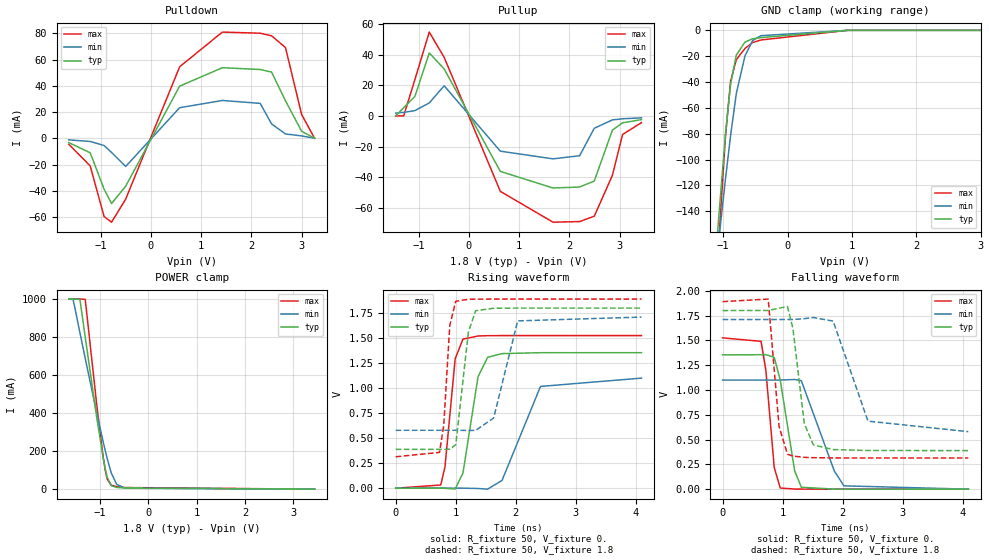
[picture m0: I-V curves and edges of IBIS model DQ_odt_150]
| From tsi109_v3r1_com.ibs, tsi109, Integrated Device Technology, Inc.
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|   MODEL DQ_odt_150
[Model]   DQ_odt_150
Model_type  I/O
Polarity   Non-Inverting
Enable   Active-Low
|   typ   min   max
|C_comp_off 3.662p 3.711p 3.594p
|C_comp_on 3.698p 3.62p 3.948p
C_comp 3.68p 3.665p 3.771p
Cref  =   20pF
Vmeas =   0.9v
Vinl  =   0.650v
Vinh  =   1.150v
[Model Spec]
[Temperature Range]   25   125   0
[Voltage Range] 1.8 1.71 1.89
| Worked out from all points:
|   slope of the pulldown table from 0 to 0.27 V, typ, clamps not added: 14 ohm
|   slope of the pullup table from 0 to 0.27 V, typ, clamps not added: 16.6 ohm
|   rising waveform, R_fixture 50, V_fixture 0.: 20-80 % time 205ps typ, 380ps min, 137ps max; typ from 0 V to 1.35 V
|   rising waveform, R_fixture 50, V_fixture 1.8: 20-80 % time 121ps typ, 188ps min, 93.3ps max; typ from 0.389 V to 1.8 V
|   falling waveform, R_fixture 50, V_fixture 0.: 20-80 % time 211ps typ, 348ps min, 129ps max; typ from 1.35 V to 0 V
|   falling waveform, R_fixture 50, V_fixture 1.8: 20-80 % time 164ps typ, 316ps min, 113ps max; typ from 1.8 V to 0.389 V
[Pulldown]
-1.636V   -3.323mA   -1.212mA   -4.599mA
-1.21V    -11.07mA   -2.446mA   -21.09mA
-933.3mV  -38.78mA   -5.524mA   -59.65mA
-784.8mV  -49.73mA   -10.81mA   -63.97mA
-502.6mV  -36.5mA    -21.48mA   -46.35mA
571.6mV   39.71mA    23.3mA     54.46mA
1.423V    53.79mA    28.81mA    80.93mA
2.176V    52.4mA     26.59mA    80.07mA
2.403V    50.45mA    10.95mA    78.12mA
2.68V     28.57mA    3.287mA    69.15mA
3.002V    5.316mA    1.795mA    18.12mA
3.26V     0A         0A         0A
[Pullup]
-1.46V    0A         1.84mA     0A
-1.301V   5.351mA    2.288mA    0A
-1.078V   12.65mA    3.443mA    23.66mA
-791.3mV  41.1mA     8.484mA    54.75mA
-494.3mV  30.7mA     19.67mA    38.23mA
624.5mV   -36.24mA   -23.04mA   -49.29mA
1.674V    -47.11mA   -28.05mA   -69.43mA
2.204V    -46.44mA   -26.01mA   -69.03mA
2.496V    -42.58mA   -8.056mA   -65.51mA
2.857V    -9.27mA    -2.618mA   -38.81mA
3.06V     -4.507mA   -1.881mA   -12.14mA
3.436V    -2.406mA   -1.258mA   -4.39mA
[GND Clamp]
-1.636V   -544mA     -441.4mA   -680mA
-1.124V   -180.9mA   -188.5mA   -209.5mA
-1.099V   -164.3mA   -176.7mA   -188.1mA
-1.074V   -147.9mA   -165mA     -167.2mA
-964.3mV  -80.44mA   -115.2mA   -82.44mA
-884.7mV  -41.57mA   -81.42mA   -39.48mA
-795.1mV  -19.11mA   -48.76mA   -22.6mA
-660.7mV  -9.028mA   -19.65mA   -14.03mA
-541.2mV  -6.508mA   -7.863mA   -9.392mA
-411.8mV  -5.625mA   -4.125mA   -7.467mA
937.8mV   0A         0A         0A
3.26V     0A         0A         0A
[Power Clamp]
-1.636V   1A         1A         1A
-1.546V   1A         997.3mA    1A
-1.407V   998.2mA    823.6mA    1A
-1.297V   799.4mA    687.6mA    998.5mA
-1.063V   382.4mA    404.2mA    451.3mA
-928mV    166.1mA    250.1mA    171.6mA
-883.1mV  105.4mA    201.6mA    98.24mA
-843.2mV  61.99mA    160.6mA    52.13mA
-758.4mV  18mA       84.13mA    19.98mA
-648.7mV  9.117mA    25.5mA     13.77mA
-474.1mV  6.076mA    5.11mA     8.511mA
3.436V    0A         0A         0A
[Ramp]
dV/dt_r .812/205.375p .66/380.602p .915/136.332p
dV/dt_f .847/163.938p .679/315.888p .946/112.754p
[Rising Waveform]
R_fixture = 50
V_fixture = 0.
0s        0V         0V         0V
750ps     198.9uV    -789.9nV   31.79mV
820ps     -1.136mV   10.99uV    212.1mV
990ps     -8.18mV    142.4uV    1.294V
1.12ns    152.2mV    239.9uV    1.49V
1.37ns    1.113V     -2.911mV   1.521V
1.53ns    1.308V     -9.701mV   1.524V
1.77ns    1.345V     78.26mV    1.525V
2.41ns    1.354V     1.017V     1.525V
4.09ns    1.354V     1.1V       1.525V
[Rising Waveform]
R_fixture = 50
V_fixture = 1.8
V_fixture_min = 1.71
V_fixture_max = 1.89
0s        388.5mV    578.6mV    314.1mV
730ps     388.1mV    578.7mV    357.9mV
800ps     387.6mV    578.7mV    630.1mV
900ps     389.8mV    578.7mV    1.627V
1ns       434.4mV    578.6mV    1.868V
1.21ns    1.561V     577.2mV    1.888V
1.33ns    1.773V     577.6mV    1.889V
1.63ns    1.798V     701.1mV    1.89V
2.03ns    1.8V       1.672V     1.89V
4.09ns    1.8V       1.71V      1.89V
[Falling Waveform]
R_fixture = 50
V_fixture = 0.
0s        1.354V     1.1V       1.525V
640ps     1.355V     1.1V       1.49V
720ps     1.356V     1.1V       1.203V
860ps     1.329V     1.1V       217.9mV
960ps     1.099V     1.1V       11.48mV
1.2ns     183.3mV    1.105V     1.23mV
1.31ns    19.37mV    1.094V     714.3uV
1.86ns    480.7uV    183.1mV    48.69uV
2.02ns    258.4uV    33.45mV    22.5uV
4.09ns    0V         23.14uV    0V
[Falling Waveform]
R_fixture = 50
V_fixture = 1.8
V_fixture_min = 1.71
V_fixture_max = 1.89
0s        1.8V       1.71V      1.89V
760ps     1.801V     1.71V      1.916V
940ps     1.824V     1.71V      632.1mV
1.08ns    1.84V      1.71V      351.9mV
1.17ns    1.623V     1.71V      333.6mV
1.36ns    662.2mV    1.718V     320.8mV
1.51ns    446.5mV    1.73V      317.2mV
1.84ns    399.2mV    1.694V     314.7mV
2.42ns    389.6mV    685.4mV    314.2mV
4.09ns    388.5mV    579.6mV    314.1mV
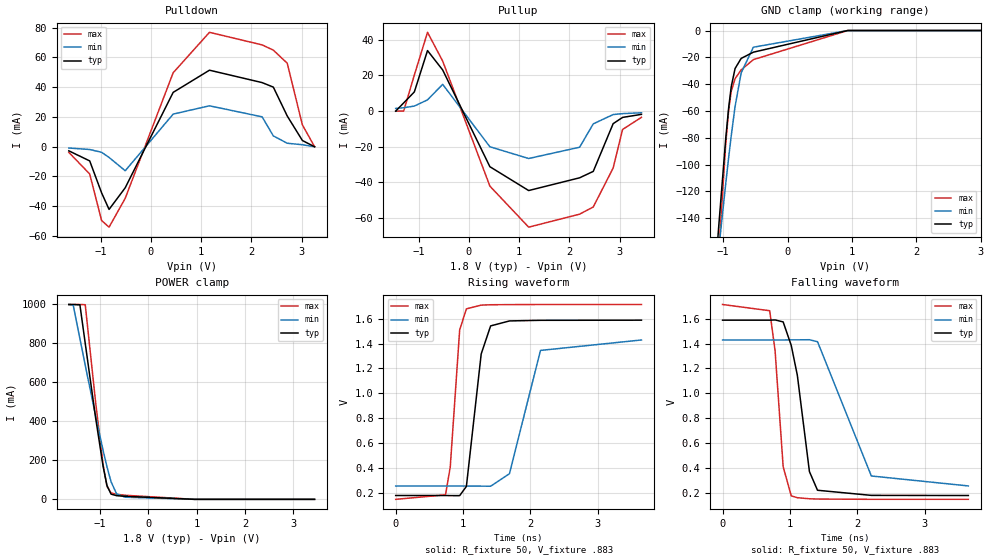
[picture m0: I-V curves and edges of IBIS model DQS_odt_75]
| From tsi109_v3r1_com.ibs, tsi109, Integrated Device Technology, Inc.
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|   MODEL DQS_odt_75
[Model]   DQS_odt_75
Model_type  I/O
Polarity   Non-Inverting
Enable   Active-Low
|   typ   min   max
|C_comp_off 3.406p 3.446p 3.36p
|C_comp_on 3.3p 3.205p 3.514p
C_comp 3.353p 3.325p 3.437p
Cref  =   20pF
Vmeas =   0.9v
Vinl  =   0.650v
Vinh  =   1.150v
[Model Spec]
[Temperature Range]   25   125   0
[Voltage Range] 1.8 1.71 1.89
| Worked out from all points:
|   slope of the pulldown table from 0 to 0.27 V, typ, clamps not added: 15.5 ohm
|   slope of the pullup table from 0 to 0.27 V, typ, clamps not added: 18.7 ohm
|   rising waveform, R_fixture 50, V_fixture .883: 20-80 % time 155ps typ, 260ps min, 111ps max; typ from 0.179 V to 1.59 V
|   falling waveform, R_fixture 50, V_fixture .883: 20-80 % time 211ps typ, 436ps min, 121ps max; typ from 1.59 V to 0.179 V
[Pulldown]
-1.636V   -2.749mA   -869.2uA   -3.779mA
-1.22V    -9.523mA   -1.848mA   -18.31mA
-982.8mV  -30.99mA   -3.738mA   -49.62mA
-834.2mV  -42.14mA   -7.191mA   -54.06mA
-512.5mV  -27.58mA   -16.15mA   -34.67mA
442.9mV   36.55mA    21.94mA    49.75mA
1.166V    51.46mA    27.52mA    76.92mA
2.215V    43.12mA    20.1mA     68.47mA
2.438V    40.09mA    7.284mA    64.95mA
2.715V    20.68mA    2.355mA    56.15mA
3.017V    4.187mA    1.352mA    14.69mA
3.26V     0A         0A         0A
[Pullup]
-1.46V    0A         1.493mA    0A
-1.301V   4.568mA    1.878mA    0A
-1.088V   10.76mA    2.811mA    20.24mA
-826mV    33.9mA     6.297mA    44.13mA
-524mV    23.04mA    14.98mA    28.03mA
416.5mV   -31.17mA   -19.99mA   -42.04mA
1.189V    -44.52mA   -26.57mA   -65.03mA
2.204V    -37.38mA   -20.25mA   -57.75mA
2.476V    -33.78mA   -7.136mA   -53.72mA
2.872V    -7.045mA   -1.945mA   -31.9mA
3.06V     -3.537mA   -1.423mA   -10.29mA
3.436V    -1.832mA   -944.9uA   -3.489mA
[GND Clamp]
-1.636V   -544.5mA   -441.7mA   -680.8mA
-1.123V   -182.1mA   -189mA     -211.5mA
-1.098V   -165.6mA   -177.3mA   -190.4mA
-1.074V   -149.3mA   -165.6mA   -169.7mA
-959.1mV  -80.05mA   -113.8mA   -84.1mA
-914.3mV  -57.55mA   -94.64mA   -59.42mA
-874.4mV  -41.91mA   -78.49mA   -45.25mA
-814.7mV  -28.31mA   -56.62mA   -35.88mA
-720.1mV  -20.78mA   -31.57mA   -29.35mA
-530.9mV  -16.15mA   -12.45mA   -21.7mA
935.2mV   0A         0A         0A
3.26V     0A         0A         0A
[Power Clamp]
-1.636V   1A         1A         1A
-1.546V   1A         997.4mA    1A
-1.407V   998.4mA    824mA      1A
-1.297V   800.3mA    688.1mA    998.9mA
-1.083V   418.1mA    428.5mA    498.6mA
-928.2mV  168.8mA    251.1mA    176.9mA
-848.4mV  71mA       166.8mA    66.16mA
-763.6mV  26.63mA    89.57mA    32.79mA
-648.9mV  18.72mA    27.94mA    26.18mA
-474.4mV  15.54mA    10.87mA    20.84mA
954.8mV   0A         0A         0A
3.436V    0A         0A         0A
[Ramp]
dV/dt_r .845/154.678p .705/260.261p .939/110.93p
dV/dt_f .845/210.589p .705/436.081p .939/121.27p
[Rising Waveform]
R_fixture = 50
V_fixture = .883
V_fixture_min = .842
V_fixture_max = .931
0s        179.2mV    255.2mV    148.5mV
740ps     179.2mV    255.2mV    184.6mV
810ps     178.4mV    255.2mV    406.7mV
950ps     178.3mV    255.3mV    1.509V
1.05ns    252.2mV    255.2mV    1.679V
1.27ns    1.317V     254.5mV    1.709V
1.41ns    1.542V     253.8mV    1.712V
1.69ns    1.582V     354.6mV    1.713V
2.15ns    1.587V     1.345V     1.714V
3.65ns    1.588V     1.429V     1.714V
[Falling Waveform]
R_fixture = 50
V_fixture = .883
V_fixture_min = .842
V_fixture_max = .931
0s        1.588V     1.429V     1.714V
700ps     1.588V     1.429V     1.664V
780ps     1.59V      1.429V     1.342V
900ps     1.574V     1.429V     410.3mV
1.02ns    1.385V     1.43V      176.4mV
1.11ns    1.147V     1.43V      161.6mV
1.29ns    371.6mV    1.431V     153mV
1.41ns    221.4mV    1.415V     150.8mV
2.21ns    180.2mV    336.1mV    148.5mV
3.65ns    179.2mV    256.1mV    148.5mV
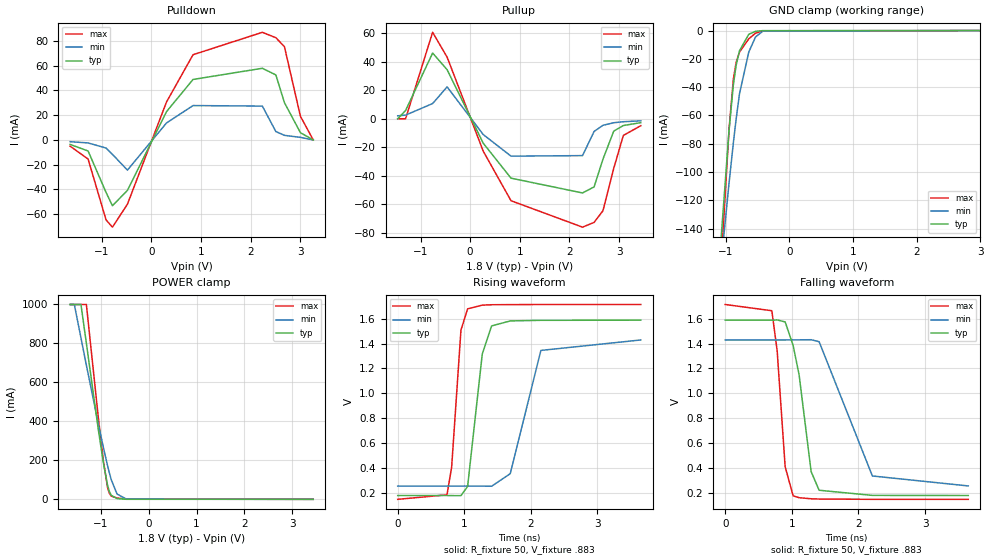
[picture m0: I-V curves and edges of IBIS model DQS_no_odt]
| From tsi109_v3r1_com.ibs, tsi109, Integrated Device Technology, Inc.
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|   MODEL DQS_no_odt
[Model]   DQS_no_odt
Model_type  I/O
Polarity   Non-Inverting
Enable   Active-Low
|   typ   min   max
|C_comp_off 3.963p 4.018p 3.887p
|C_comp_on 3.3p 3.205p 3.514p
C_comp 3.631p 3.611p 3.7p
Cref  =   20pF
Vmeas =   0.9v
Vinl  =   0.650v
Vinh  =   1.150v
[Model Spec]
[Temperature Range]   25   125   0
[Voltage Range] 1.8 1.71 1.89
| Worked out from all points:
|   slope of the pulldown table from 0 to 0.27 V, typ, clamps not added: 13.2 ohm
|   slope of the pullup table from 0 to 0.27 V, typ, clamps not added: 15.4 ohm
|   GND clamp passes 1 mA (typ) near -0.57 V on its own axis
|   POWER clamp passes 1 mA (typ) near -0.54 V on its own axis
|   rising waveform, R_fixture 50, V_fixture .883: 20-80 % time 155ps typ, 260ps min, 111ps max; typ from 0.179 V to 1.59 V
|   falling waveform, R_fixture 50, V_fixture .883: 20-80 % time 211ps typ, 436ps min, 121ps max; typ from 1.59 V to 0.179 V
[Pulldown]
-1.636V   -3.649mA   -1.42mA    -5.055mA
-1.275V   -8.922mA   -2.436mA   -15.46mA
-913.5mV  -42.38mA   -6.562mA   -64.55mA
-784.8mV  -53.15mA   -11.67mA   -70.44mA
-482.8mV  -40.74mA   -24.38mA   -51.92mA
304.3mV   22.85mA    13.69mA    30.62mA
838.9mV   48.83mA    27.75mA    68.81mA
2.235V    57.86mA    27.32mA    86.89mA
2.507V    52.5mA     6.75mA     82.54mA
2.68V     30.08mA    3.705mA    75.24mA
3.002V    5.838mA    2.051mA    19.08mA
3.26V     0A         0A         0A
[Pullup]
-1.46V    0A         2.056mA    0A
-1.301V   5.791mA    2.542mA    0A
-756.7mV  46.08mA    10.65mA    60.6mA
-464.6mV  34.39mA    22.34mA    43.2mA
263.1mV   -17.14mA   -11.08mA   -22.74mA
822.5mV   -41.66mA   -26.22mA   -57.48mA
2.263V    -52.03mA   -25.85mA   -76.01mA
2.496V    -47.78mA   -8.921mA   -72.68mA
2.674V    -28.4mA    -4.593mA   -64.52mA
2.892V    -8.672mA   -2.791mA   -34.76mA
3.085V    -4.751mA   -2.084mA   -11.69mA
3.436V    -2.732mA   -1.461mA   -4.887mA
[GND Clamp]
-1.636V   -543.7mA   -441.2mA   -679.6mA
-1.113V   -173.3mA   -183.3mA   -199.6mA
-1.089V   -157.2mA   -171.9mA   -178.9mA
-1.065V   -141.4mA   -160.5mA   -158.5mA
-948.9mV  -70.59mA   -107.9mA   -69.79mA
-881.1mV  -38.31mA   -79.34mA   -34.33mA
-837.5mV  -24.54mA   -62.52mA   -22.45mA
-784.3mV  -14.23mA   -44.56mA   -15.18mA
-639mV    -2.666mA   -15.21mA   -5.883mA
-532.5mV  -543.1uA   -4.536mA   -1.841mA
-416.4mV  -69.24uA   -425.6uA   -218.8uA
3.26V     0A         0A         0A
[Power Clamp]
-1.636V   1A         1A         1A
-1.549V   1A         1A         1A
-1.411V   1A         828.4mA    1A
-1.298V   800.8mA    688.6mA    1A
-1.047V   355mA      385.4mA    415.3mA
-944.5mV  189.4mA    267.9mA    200.5mA
-857.4mV  74.25mA    174.4mA    62.22mA
-821.5mV  42.19mA    138.8mA    31.99mA
-780.5mV  20.7mA     101.5mA    16.68mA
-657.5mV  3.818mA    26.99mA    6.851mA
-462.8mV  270uA      1.332mA    1.058mA
3.436V    0A         0A         0A
[Ramp]
dV/dt_r .845/154.678p .705/260.261p .939/110.93p
dV/dt_f .845/210.589p .705/436.081p .939/121.27p
[Rising Waveform]
R_fixture = 50
V_fixture = .883
V_fixture_min = .842
V_fixture_max = .931
0s        179.2mV    255.2mV    148.5mV
740ps     179.2mV    255.2mV    184.6mV
810ps     178.4mV    255.2mV    406.7mV
950ps     178.3mV    255.3mV    1.509V
1.05ns    252.2mV    255.2mV    1.679V
1.27ns    1.317V     254.5mV    1.709V
1.41ns    1.542V     253.8mV    1.712V
1.69ns    1.582V     354.6mV    1.713V
2.15ns    1.587V     1.345V     1.714V
3.65ns    1.588V     1.429V     1.714V
[Falling Waveform]
R_fixture = 50
V_fixture = .883
V_fixture_min = .842
V_fixture_max = .931
0s        1.588V     1.429V     1.714V
700ps     1.588V     1.429V     1.664V
780ps     1.59V      1.429V     1.342V
900ps     1.574V     1.429V     410.3mV
1.02ns    1.385V     1.43V      176.4mV
1.11ns    1.147V     1.43V      161.6mV
1.29ns    371.6mV    1.431V     153mV
1.41ns    221.4mV    1.415V     150.8mV
2.21ns    180.2mV    336.1mV    148.5mV
3.65ns    179.2mV    256.1mV    148.5mV
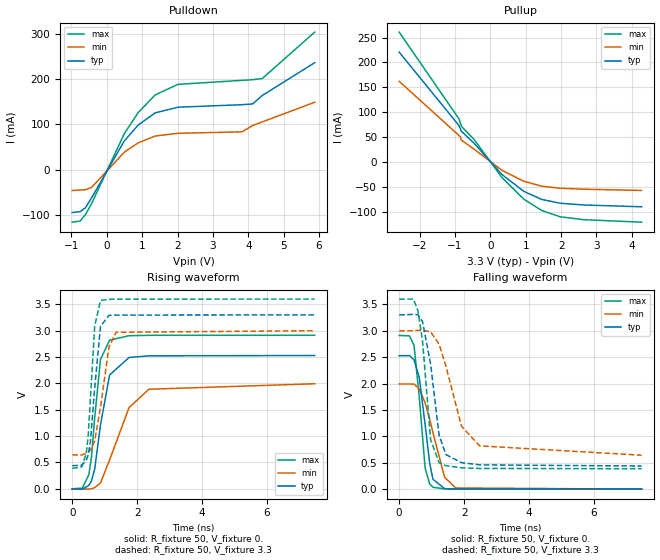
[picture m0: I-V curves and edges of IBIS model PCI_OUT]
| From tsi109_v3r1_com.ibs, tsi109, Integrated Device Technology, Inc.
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|   MODEL PCI_OUT
[Model]   PCI_OUT
Model_type  Output
C_comp 4.536p 4.267p 4.874p
Polarity   Non-Inverting
Enable   Active-High
Vmeas =   1.50V
Cref =   10pF
Rref =   50
Vref=   0.0V
[Model Spec]
[Temperature Range]   25.0   125.0   0.0
[POWER Clamp Reference]   3.30V   3.00V   3.60V
[GND Clamp Reference]   0.00V   0.00V   0.00V
[Voltage Range] 3.3 3. 3.6
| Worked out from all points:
|   slope of the pulldown table from 0 to 0.495 V, typ, clamps not added: 7.81 ohm
|   slope of the pullup table from 0 to 0.495 V, typ, clamps not added: 13.9 ohm
|   rising waveform, R_fixture 50, V_fixture 0.: 20-80 % time 365ps typ, 722ps min, 252ps max; typ from 0 V to 2.53 V
|   rising waveform, R_fixture 50, V_fixture 3.3: 20-80 % time 214ps typ, 317ps min, 179ps max; typ from 0.438 V to 3.3 V
|   falling waveform, R_fixture 50, V_fixture 0.: 20-80 % time 295ps typ, 484ps min, 225ps max; typ from 2.53 V to 0 V
|   falling waveform, R_fixture 50, V_fixture 3.3: 20-80 % time 338ps typ, 623ps min, 255ps max; typ from 3.3 V to 0.438 V
[Pulldown]
-976.9mV  -94.66mA   -46.06mA   -115.9mA
-755.1mV  -92.67mA   -44.99mA   -113.3mA
-602.6mV  -83.91mA   -44.25mA   -98.97mA
-429.3mV  -61.97mA   -39.17mA   -74.63mA
492.7mV   63.11mA    38.33mA    79.1mA
887.8mV   98.31mA    59.1mA     125.8mA
1.366V    125.1mA    74.02mA    164.6mA
2.011V    137.6mA    80.08mA    188mA
3.82V     143.1mA    83.35mA    196.8mA
4.125V    144.9mA    97.25mA    198.3mA
4.395V    163.4mA    105.2mA    200.8mA
5.879V    235.8mA    148.6mA    303.2mA
[Pullup]
-2.579V   220.8mA    162.3mA    261mA
-887.4mV  73.58mA    53.57mA    86.96mA
-845.8mV  67.08mA    50.84mA    78.03mA
-825mV    62.16mA    44.44mA    73.93mA
-797.3mV  60.62mA    43.09mA    70.27mA
-457.6mV  37.9mA     26.06mA    45.41mA
325.7mV   -24.64mA   -16.22mA   -30.66mA
942.6mV   -58.4mA    -38.19mA   -74.08mA
1.449V    -74.68mA   -48.2mA    -96.82mA
1.969V    -82.31mA   -52.22mA   -109.5mA
2.641V    -85.87mA   -54.22mA   -115.4mA
4.277V    -89.5mA    -56.68mA   -120.4mA
[Ramp]
dV/dt_r 1.518/365.233p 1.196/721.027p 1.748/252.143p
dV/dt_f 1.717/337.435p 1.415/622.991p 1.928/255.277p
[Rising Waveform]
R_fixture = 50
V_fixture = 0.
0s        0V         0V         0V
310ps     -6.844mV   -4.37mV    13.04mV
510ps     64.12mV    -5.727mV   266.9mV
590ps     148.6mV    876.9uV    593.8mV
690ps     372.2mV    21.72mV    1.349V
870ps     1.216V     113.8mV    2.456V
1.15ns    2.159V     548.1mV    2.82V
1.75ns    2.492V     1.542V     2.905V
2.36ns    2.523V     1.889V     2.912V
7.47ns    2.529V     1.993V     2.913V
[Rising Waveform]
R_fixture = 50
V_fixture = 3.3
V_fixture_min = 3.
V_fixture_max = 3.6
0s        438.2mV    642.1mV    387.4mV
290ps     446mV      642.8mV    414mV
430ps     538.7mV    670.7mV    668.8mV
490ps     644.8mV    695.1mV    995.8mV
560ps     900.2mV    739mV      1.723V
690ps     1.912V     905.9mV    3.085V
870ps     3.083V     1.55V      3.573V
1.13ns    3.29V      2.691V     3.595V
1.35ns    3.296V     2.969V     3.598V
7.47ns    3.3V       3V         3.6V
[Falling Waveform]
R_fixture = 50
V_fixture = 0.
0s        2.529V     1.993V     2.913V
320ps     2.53V      1.993V     2.904V
460ps     2.449V     1.991V     2.721V
620ps     2.114V     1.898V     1.741V
800ps     1.225V     1.639V     400.5mV
940ps     494.5mV    1.326V     98.54mV
1.04ns    189.4mV    1.072V     36.42mV
1.4ns     9.436mV    226.5mV    4.559mV
1.74ns    3.211mV    22.96mV    1.848mV
7.47ns    1.068uV    15.07uV    0V
[Falling Waveform]
R_fixture = 50
V_fixture = 3.3
V_fixture_min = 3.
V_fixture_max = 3.6
0s        3.3V       3V         3.6V
440ps     3.312V     3.002V     3.602V
580ps     3.305V     3.009V     3.381V
720ps     3.177V     3.011V     2.812V
970ps     2.367V     2.981V     935.2mV
1.23ns    1.023V     2.749V     502.3mV
1.44ns    655.6mV    2.332V     445.3mV
1.92ns    502.3mV    1.193V     404.6mV
2.48ns    460.6mV    820.5mV    392.7mV
7.47ns    438.2mV    643.1mV    387.4mV
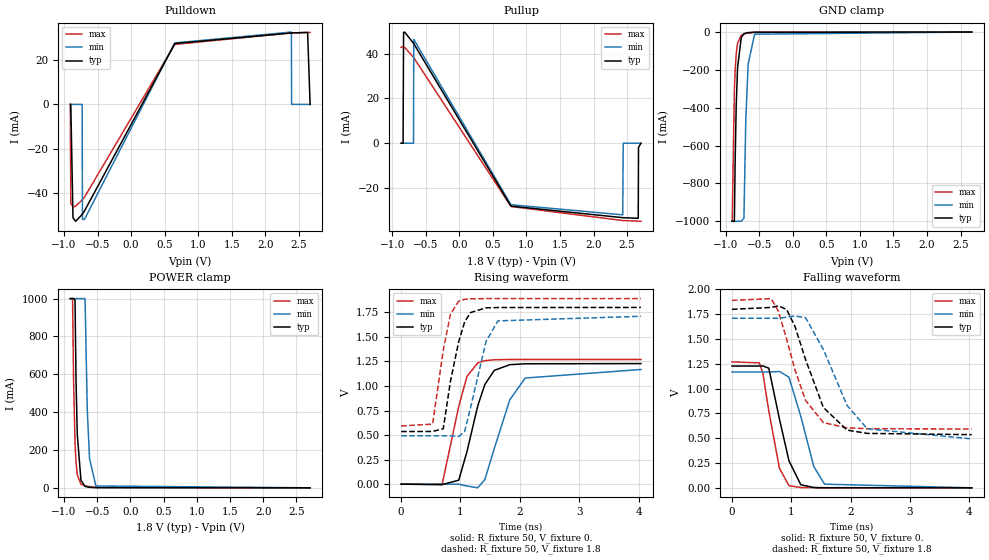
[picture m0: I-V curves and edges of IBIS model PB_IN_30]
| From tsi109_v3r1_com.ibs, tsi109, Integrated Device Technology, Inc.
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[Model]   PB_IN_30
Model_type  Input
Polarity   Non-Inverting
Enable   Active-High
|   typ   min   max
|C_comp_off 3.714p 3.514p 3.979p
|C_comp_on 4.306p 3.899p 4.757p
C_comp 4.01p 3.706p 4.368p
Vinl  =   0.300v
Vinh  =   1.500v
Vmeas =   0.9000V
Cref  =   1.0pF
Rref  =   50.0000
Vref  =   0.0V
[Model Spec]
[Temperature Range]   25   125   0
[Voltage Range] 1.8 1.71 1.89
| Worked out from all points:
|   slope of the pulldown table from 0 to 0.27 V, typ, clamps not added: 16.6 ohm
|   slope of the pullup table from 0 to 0.27 V, typ, clamps not added: 18.8 ohm
|   GND clamp passes 1 mA (typ) near -0.59 V on its own axis
|   POWER clamp passes 1 mA (typ) near -0.54 V on its own axis
|   rising waveform, R_fixture 50, V_fixture 0.: 20-80 % time 312ps typ, 380ps min, 254ps max; typ from 0 V to 1.23 V
|   rising waveform, R_fixture 50, V_fixture 1.8: 20-80 % time 240ps typ, 282ps min, 201ps max; typ from 0.536 V to 1.8 V
|   falling waveform, R_fixture 50, V_fixture 0.: 20-80 % time 255ps typ, 300ps min, 214ps max; typ from 1.23 V to 0 V
|   falling waveform, R_fixture 50, V_fixture 1.8: 20-80 % time 451ps typ, 545ps min, 401ps max; typ from 1.8 V to 0.536 V
[Pulldown]
-905.9mV  0A         0A         0A
-898.7mV  0A         0A         -44.45mA
-866.2mV  -51.03mA   0A         -46.14mA
-826.5mV  -52.6mA    0A         -45.84mA
-728.9mV  -49.53mA   0A         -42.98mA
-725.3mV  -49.37mA   -51.66mA   -42.85mA
-696.4mV  -48.04mA   -51.83mA   -41.82mA
650.9mV   27.37mA    27.66mA    26.99mA
2.388V    32.15mA    32.55mA    32.16mA
2.392V    32.16mA    0A         32.16mA
2.63V     32.37mA    0A         32.35mA
2.667V    0A         0A         32.38mA
[Pullup]
-866.5mV  0A         0A         42.86mA
-837.6mV  0A         0A         43.24mA
-830.4mV  49.49mA    0A         43.16mA
-815.9mV  49.71mA    0A         42.9mA
-682.3mV  44.71mA    0A         38.42mA
-678.7mV  44.53mA    46.42mA    38.28mA
769.8mV   -28.13mA   -27.5mA    -28.3mA
2.435V    -33.28mA   -32.01mA   -34.56mA
2.442V    -33.29mA   0A         -34.57mA
2.666V    -33.56mA   0A         -34.85mA
2.67V     -1.866mA   0A         -34.86mA
2.706V    0A         0A         -34.9mA
[GND Clamp]
-905.9mV  -1A        -1A        -1A
-902mV    -1A        -1A        -992.1mA
-870.3mV  -1A        -1A        -307.9mA
-858.4mV  -673.7mA   -1A        -200.2mA
-842.6mV  -383.8mA   -1A        -114.8mA
-822.8mV  -189.2mA   -1A        -59.98mA
-767.4mV  -28.81mA   -1A        -16.38mA
-727.8mV  -9.573mA   -983.7mA   -10.24mA
-700.1mV  -5.335mA   -460.2mA   -8.025mA
-664.4mV  -2.969mA   -168.9mA   -5.929mA
-569.4mV  -685.4uA   -11.35mA   -2.094mA
2.667V    0A         0A         0A
[Power Clamp]
-905.9mV  1A         1A         1A
-872mV    1A         1A         1A
-856.6mV  1A         1A         562.1mA
-835mV    992.8mA    1A         239.7mA
-819.6mV  564mA      1A         133.6mA
-801.1mV  283.2mA    1A         69.73mA
-745.5mV  39.72mA    1A         18.58mA
-683.9mV  7.976mA    1A         10.28mA
-649.9mV  4.587mA    407.5mA    8.166mA
-616mV    2.952mA    153.8mA    6.414mA
-520.4mV  744.8uA    9.906mA    2.557mA
2.706V    0A         0A         0A
[Ramp]
dV/dt_r .737/312.486p .701/380.002p .762/253.692p
dV/dt_f .758/450.715p .73/545.704p .778/401.037p
[Rising Waveform]
R_fixture = 50
V_fixture = 0.
0s        0V         0V         0V
690ps     -5.012mV   -102.8uV   -3.358mV
970ps     40.25mV    -263.4uV   790.8mV
1.11ns    333.3mV    -19.1mV    1.099V
1.29ns    796.1mV    -37.56mV   1.235V
1.41ns    1.015V     46.4mV     1.258V
1.57ns    1.159V     364.1mV    1.267V
1.83ns    1.217V     858.3mV    1.27V
2.09ns    1.226V     1.081V     1.27V
4.04ns    1.228V     1.168V     1.27V
[Rising Waveform]
R_fixture = 50
V_fixture = 1.8
V_fixture_min = 1.71
V_fixture_max = 1.89
0s        536.1mV    492.7mV    593mV
530ps     536.7mV    492.7mV    611.7mV
710ps     564.5mV    493mV      1.365V
830ps     1.046V     493.4mV    1.729V
970ps     1.452V     485.2mV    1.864V
1.07ns    1.653V     537.9mV    1.883V
1.17ns    1.748V     780.2mV    1.888V
1.43ns    1.796V     1.453V     1.89V
1.63ns    1.799V     1.663V     1.89V
4.04ns    1.8V       1.71V      1.89V
[Falling Waveform]
R_fixture = 50
V_fixture = 0.
0s        1.228V     1.168V     1.27V
460ps     1.228V     1.168V     1.26V
520ps     1.229V     1.168V     1.158V
620ps     1.207V     1.168V     776mV
800ps     693.3mV    1.173V     196.3mV
960ps     273mV      1.116V     22.21mV
1.16ns    30.76mV    719.7mV    2.648mV
1.38ns    3.13mV     212.7mV    942.3uV
1.56ns    1.376mV    37.03mV    438.8uV
4.04ns    0V         9.409uV    0V
[Falling Waveform]
R_fixture = 50
V_fixture = 1.8
V_fixture_min = 1.71
V_fixture_max = 1.89
0s        1.8V       1.71V      1.89V
660ps     1.819V     1.71V      1.908V
780ps     1.835V     1.709V     1.783V
920ps     1.799V     1.721V     1.502V
1.06ns    1.63V      1.733V     1.192V
1.24ns    1.293V     1.716V     881.2mV
1.54ns    809.7mV    1.394V     657.5mV
1.94ns    582mV      829.7mV    604.6mV
2.28ns    548.9mV    595mV      596.1mV
4.04ns    536.1mV    493.7mV    593mV
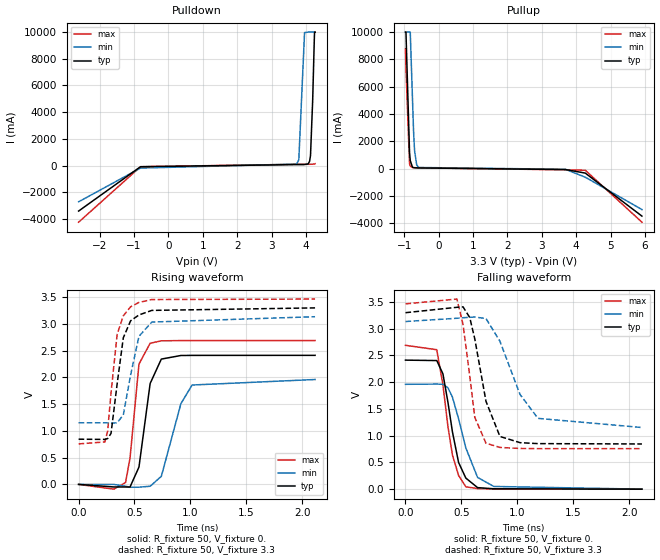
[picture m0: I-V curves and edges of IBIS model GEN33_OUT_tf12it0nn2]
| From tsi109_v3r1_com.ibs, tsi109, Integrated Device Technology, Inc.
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|   MODEL GEN33_OUT_tf12it0nn2
[Model]   GEN33_OUT_tf12it0nn2
Model_type  Output
C_comp 1.766p 1.699p 1.803p
Polarity   Non-Inverting
Enable   Active-High
Vmeas =   1.65V
|   typ   min   max
[Model Spec]
[Temperature Range]   25   125   0
[Voltage Range] 3.3 3.135 3.465
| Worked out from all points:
|   slope of the pulldown table from 0 to 0.495 V, typ, clamps not added: 15.3 ohm
|   slope of the pullup table from 0 to 0.495 V, typ, clamps not added: 16.5 ohm
|   rising waveform, R_fixture 50, V_fixture 0.: 20-80 % time 92.1ps typ, 147ps min, 70.9ps max; typ from 0 V to 2.41 V
|   rising waveform, R_fixture 50, V_fixture 3.3: 20-80 % time 90.2ps typ, 107ps min, 84.6ps max; typ from 0.845 V to 3.3 V
|   falling waveform, R_fixture 50, V_fixture 0.: 20-80 % time 121ps typ, 155ps min, 109ps max; typ from 2.41 V to 0 V
|   falling waveform, R_fixture 50, V_fixture 3.3: 20-80 % time 137ps typ, 233ps min, 99.2ps max; typ from 3.3 V to 0.845 V
[Pulldown]
-2.61V    -3.409A    -2.716A    -4.243A
-810.3mV  -87.57mA   -187.9mA   -85.67mA
3.727V    74mA       112.5mA    93.78mA
3.79V     74.17mA    432.2mA    93.9mA
3.957V    76.42mA    9.961A     94.66mA
4.061V    125.5mA    10A        96.09mA
4.103V    316.6mA    10A        96.92mA
4.13V     753.6mA    10A        97.61mA
4.193V    4.893A     10A        100.9mA
4.242V    9.621A     10A        115.9mA
4.248V    10A        10A        121.4mA
4.262V    10A        10A        138.9mA
[Pullup]
-962.4mV  10A        10A        8.778A
-948.5mV  10A        10A        7.327A
-844.3mV  1.168A     10A        338mA
-823.4mV  578.6mA    10A        181.5mA
-760.9mV  102.5mA    5.267A     72.23mA
-726.1mV  64.45mA    2.651A     63.16mA
-698.3mV  54.26mA    1.31A      59.61mA
-635.8mV  45.94mA    254.2mA    53.96mA
-580.2mV  41.66mA    74.14mA    49.33mA
3.686V    -76.22mA   -58.07mA   -98.48mA
4.263V    -336.6mA   -638.2mA   -127.6mA
5.91V     -3.49A     -3.011A    -3.936A
[Ramp]
dV/dt_r 1.448/92.133p 1.177/146.688p 1.614/70.781p
dV/dt_f 1.473/136.637p 1.19/233.06p 1.625/99.242p
[Rising Waveform]
R_fixture = 50
V_fixture = 0.
0s        514.3nV    829.9nV    0V
315ps     -47.89mV   -434.8uV   -89.09mV
420ps     -48.36mV   -33.69mV   35.24mV
460ps     -48.53mV   -53.68mV   490.4mV
540ps     324.4mV    -51.57mV   2.25V
640ps     1.887V     -34.35mV   2.639V
740ps     2.343V     150.7mV    2.684V
915ps     2.41V      1.509V     2.689V
1.015ns   2.412V     1.858V     2.689V
2.115ns   2.413V     1.961V     2.689V
[Rising Waveform]
R_fixture = 50
V_fixture = 3.3
V_fixture_min = 3.135
V_fixture_max = 3.465
0s        845.1mV    1.152V     757.2mV
235ps     841.3mV    1.152V     794.1mV
260ps     857.8mV    1.15V      998.3mV
290ps     953.2mV    1.146V     1.714V
345ps     1.882V     1.152V     2.807V
400ps     2.742V     1.299V     3.152V
465ps     3.058V     2.044V     3.32V
540ps     3.168V     2.769V     3.402V
655ps     3.253V     3.035V     3.456V
2.115ns   3.3V       3.135V     3.465V
[Falling Waveform]
R_fixture = 50
V_fixture = 0.
0s        2.413V     1.961V     2.69V
280ps     2.405V     1.965V     2.608V
335ps     2.157V     1.962V     1.951V
380ps     1.623V     1.895V     1.168V
420ps     1.072V     1.722V     639.2mV
475ps     498.9mV    1.318V     256.4mV
540ps     206.9mV    770.5mV    44.37mV
645ps     29.04mV    219.5mV    10.6mV
790ps     7.195mV    50.93mV    2.931mV
2.115ns   27.36uV    31.28uV    31.61uV
[Falling Waveform]
R_fixture = 50
V_fixture = 3.3
V_fixture_min = 3.135
V_fixture_max = 3.465
0s        3.3V       3.135V     3.465V
460ps     3.401V     3.196V     3.555V
515ps     3.409V     3.206V     3.079V
575ps     3.209V     3.214V     2.116V
620ps     2.81V      3.219V     1.343V
720ps     1.644V     3.191V     859.4mV
845ps     985.4mV    2.766V     780.4mV
1.025ns   869.6mV    1.77V      761.2mV
1.185ns   851.7mV    1.324V     758.1mV
2.115ns   845.2mV    1.153V     757.3mV
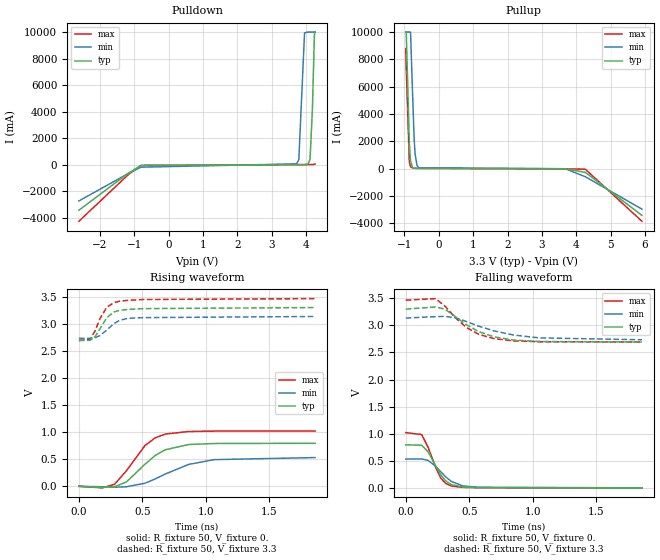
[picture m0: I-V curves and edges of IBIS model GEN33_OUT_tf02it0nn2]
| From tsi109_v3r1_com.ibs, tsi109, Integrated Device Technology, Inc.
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|   MODEL GEN33_OUT_tf02it0nn2
[Model]   GEN33_OUT_tf02it0nn2
Model_type  Output
C_comp 1.269p 1.201p 1.348p
Polarity   Non-Inverting
Enable   Active-High
Vmeas =   1.65V
|   typ   min   max
[Model Spec]
[Temperature Range]   25   125   0
[Voltage Range] 3.3 3.135 3.465
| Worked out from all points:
|   slope of the pulldown table from 0 to 0.495 V, typ, clamps not added: 80.3 ohm
|   slope of the pullup table from 0 to 0.495 V, typ, clamps not added: 77.1 ohm
|   rising waveform, R_fixture 50, V_fixture 0.: 20-80 % time 230ps typ, 323ps min, 202ps max; typ from 0 V to 0.794 V
|   rising waveform, R_fixture 50, V_fixture 3.3: 20-80 % time 107ps typ, 127ps min, 97.8ps max; typ from 2.69 V to 3.3 V
|   falling waveform, R_fixture 50, V_fixture 0.: 20-80 % time 118ps typ, 144ps min, 106ps max; typ from 0.794 V to 0 V
|   falling waveform, R_fixture 50, V_fixture 3.3: 20-80 % time 275ps typ, 373ps min, 237ps max; typ from 3.3 V to 2.69 V
[Pulldown]
-2.615V   -3.418A    -2.722A    -4.253A
-1.161V   -606.6mA   -632.5mA   -705mA
-806.7mV  -52.97mA   -178.3mA   -41.43mA
3.727V    12.4mA     72.18mA    15.71mA
3.79V     12.5mA     393.1mA    15.74mA
3.957V    14.56mA    9.941A     16.24mA
4.061V    64.24mA    10A        17.5mA
4.117V    425.1mA    10A        18.55mA
4.186V    4.2A       10A        21.45mA
4.242V    9.606A     10A        37.23mA
4.249V    10A        10A        43.03mA
4.263V    10A        10A        60.7mA
[Pullup]
-962.9mV  10A        10A        8.788A
-949mV    10A        10A        7.336A
-858.6mV  1.837A     10A        504mA
-823.8mV  545.2mA    10A        134.9mA
-761.2mV  62.8mA     5.27A      25.81mA
-719.5mV  22.48mA    2.226A     17.52mA
-691.7mV  15.29mA    1.075A     15.6mA
-636mV    10.95mA    231.2mA    13.39mA
-580.4mV  9.367mA    51.69mA    11.67mA
3.682V    -16.34mA   -17.56mA   -21.1mA
4.267V    -281.8mA   -602.6mA   -51.68mA
5.915V    -3.435A    -2.975A    -3.865A
[Ramp]
dV/dt_r .476/230.063p .318/323.059p .612/201.762p
dV/dt_f .365/274.969p .241/374.442p .463/237.433p
[Rising Waveform]
R_fixture = 50
V_fixture = 0.
0s        0V         0V         0V
185ps     -20.24mV   -8.288mV   -28.27mV
280ps     -9.948mV   -16.97mV   35.78mV
375ps     81.29mV    -8.553mV   288.1mV
520ps     405.4mV    56.43mV    750.9mV
600ps     567.4mV    134.5mV    892.9mV
680ps     674.4mV    226.6mV    964.2mV
865ps     771.2mV    404.2mV    1.012V
1.065ns   790.1mV    492.3mV    1.019V
1.86ns    793.7mV    530.4mV    1.02V
[Rising Waveform]
R_fixture = 50
V_fixture = 3.3
V_fixture_min = 3.135
V_fixture_max = 3.465
0s        2.691V     2.733V     2.693V
90ps      2.696V     2.731V     2.719V
130ps     2.771V     2.745V     2.879V
165ps     2.904V     2.782V     3.093V
220ps     3.112V     2.884V     3.306V
275ps     3.217V     3.003V     3.389V
320ps     3.248V     3.063V     3.416V
385ps     3.266V     3.101V     3.433V
505ps     3.28V      3.114V     3.448V
1.86ns    3.3V       3.135V     3.465V
[Falling Waveform]
R_fixture = 50
V_fixture = 0.
0s        793.7mV    530.7mV    1.02V
125ps     786.7mV    534mV      983.8mV
175ps     667.7mV    508.2mV    753.1mV
235ps     410.5mV    397.6mV    379.8mV
275ps     241.2mV    298.2mV    183.1mV
315ps     125.8mV    201.9mV    81.41mV
360ps     58.96mV    116.5mV    33.3mV
450ps     14.43mV    36.11mV    8.764mV
575ps     4.444mV    9.419mV    3.204mV
1.86ns    2.98uV     32.28uV    1.306uV
[Falling Waveform]
R_fixture = 50
V_fixture = 3.3
V_fixture_min = 3.135
V_fixture_max = 3.465
0s        3.3V       3.135V     3.465V
235ps     3.339V     3.161V     3.494V
310ps     3.298V     3.166V     3.353V
395ps     3.152V     3.139V     3.13V
480ps     3.008V     3.069V     2.958V
575ps     2.884V     2.985V     2.835V
695ps     2.788V     2.898V     2.754V
850ps     2.728V     2.821V     2.713V
1.05ns    2.702V     2.769V     2.698V
1.86ns    2.692V     2.734V     2.693V
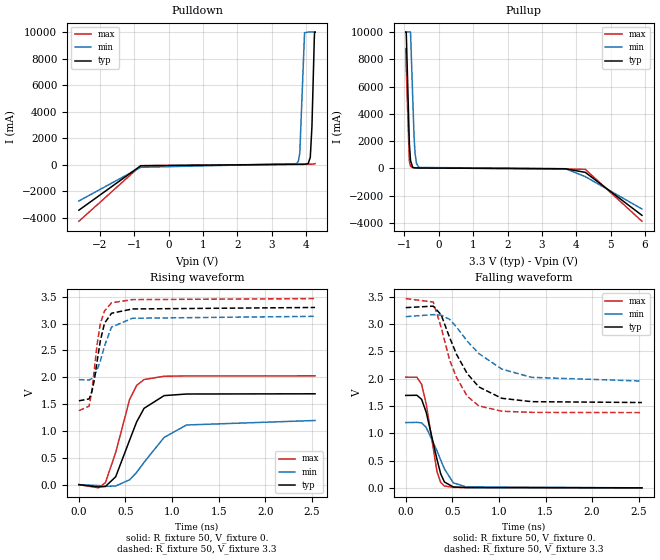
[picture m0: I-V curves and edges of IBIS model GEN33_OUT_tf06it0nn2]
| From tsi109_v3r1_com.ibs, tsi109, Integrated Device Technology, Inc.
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|   MODEL GEN33_OUT_tf06it0nn2
[Model]   GEN33_OUT_tf06it0nn2
Model_type  Output
C_comp 1.649p 1.589p 1.712p
Polarity   Non-Inverting
Enable   Active-High
Vmeas =   1.65V
|   typ   min   max
[Model Spec]
[Temperature Range]   25   125   0
[Voltage Range] 3.3 3.135 3.465
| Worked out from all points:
|   slope of the pulldown table from 0 to 0.495 V, typ, clamps not added: 28.4 ohm
|   slope of the pullup table from 0 to 0.495 V, typ, clamps not added: 32.6 ohm
|   rising waveform, R_fixture 50, V_fixture 0.: 20-80 % time 229ps typ, 345ps min, 188ps max; typ from 0 V to 1.69 V
|   rising waveform, R_fixture 50, V_fixture 3.3: 20-80 % time 103ps typ, 130ps min, 93.2ps max; typ from 1.56 V to 3.3 V
|   falling waveform, R_fixture 50, V_fixture 0.: 20-80 % time 136ps typ, 179ps min, 113ps max; typ from 1.69 V to 0 V
|   falling waveform, R_fixture 50, V_fixture 3.3: 20-80 % time 317ps typ, 447ps min, 247ps max; typ from 3.3 V to 1.56 V
[Pulldown]
-2.613V   -3.415A    -2.72A     -4.25A
-812.4mV  -68.54mA   -186.8mA   -62.34mA
3.727V    37.09mA    88.44mA    47.02mA
3.776V    37.18mA    283.1mA    47.08mA
3.818V    37.33mA    860.9mA    47.13mA
3.957V    39.38mA    9.949A     47.72mA
4.061V    88.7mA     10A        49.07mA
4.124V    568.3mA    10A        50.35mA
4.172V    2.879A     10A        52.15mA
4.242V    9.613A     10A        69.07mA
4.249V    10A        10A        74.6mA
4.263V    10A        10A        91.81mA
[Pullup]
-962.7mV  10A        10A        8.783A
-948.8mV  10A        10A        7.332A
-858.4mV  1.841A     10A        518.3mA
-823.7mV  557.1mA    10A        151.4mA
-761.1mV  77.1mA     5.268A     42.71mA
-719.4mV  36.46mA    2.228A     33.75mA
-691.6mV  28.89mA    1.08A      31.35mA
-649.9mV  24.53mA    348.5mA    28.88mA
-580.3mV  21.11mA    59.76mA    25.36mA
3.688V    -38.12mA   -32.97mA   -49.24mA
4.265V    -301.7mA   -615.6mA   -79.37mA
5.913V    -3.455A    -2.989A    -3.891A
[Ramp]
dV/dt_r 1.015/228.756p .717/344.077p 1.216/188.269p
dV/dt_f 1.043/317.593p .709/447.763p 1.253/247.491p
[Rising Waveform]
R_fixture = 50
V_fixture = 0.
0s        714nV      0V         719.3nV
210ps     -43.01mV   -16.83mV   -59.52mV
285ps     -33.8mV    -32.41mV   36.83mV
395ps     146.5mV    -24.9mV    597.9mV
545ps     831.3mV    91.18mV    1.59V
620ps     1.169V     228.1mV    1.848V
700ps     1.422V     416.9mV    1.958V
915ps     1.658V     879.5mV    2.019V
1.155ns   1.688V     1.111V     2.025V
2.535ns   1.692V     1.195V     2.026V
[Rising Waveform]
R_fixture = 50
V_fixture = 3.3
V_fixture_min = 3.135
V_fixture_max = 3.465
0s        1.562V     1.954V     1.377V
110ps     1.596V     1.949V     1.463V
140ps     1.738V     1.977V     1.745V
165ps     1.94V      2.03V      2.134V
195ps     2.287V     2.132V     2.605V
230ps     2.679V     2.3V       2.999V
275ps     3.006V     2.581V     3.234V
350ps     3.192V     2.934V     3.387V
575ps     3.272V     3.099V     3.446V
2.535ns   3.3V       3.135V     3.465V
[Falling Waveform]
R_fixture = 50
V_fixture = 0.
0s        1.692V     1.195V     2.026V
120ps     1.695V     1.199V     2.025V
170ps     1.621V     1.19V      1.896V
220ps     1.381V     1.106V     1.531V
335ps     521.7mV    677.5mV    297mV
375ps     257mV      507.7mV    97.18mV
415ps     106.6mV    346.4mV    32.96mV
510ps     16.11mV    92.43mV    9.22mV
650ps     5.688mV    15.43mV    3.898mV
2.535ns   12.24uV    11.96uV    22.76uV
[Falling Waveform]
R_fixture = 50
V_fixture = 3.3
V_fixture_min = 3.135
V_fixture_max = 3.465
0s        3.3V       3.135V     3.465V
295ps     3.327V     3.171V     3.402V
380ps     3.168V     3.161V     2.939V
470ps     2.756V     3.087V     2.344V
545ps     2.444V     2.944V     2.02V
660ps     2.091V     2.686V     1.677V
785ps     1.847V     2.458V     1.5V
1.03ns    1.64V      2.175V     1.403V
1.35ns    1.578V     2.023V     1.382V
2.535ns   1.562V     1.955V     1.377V
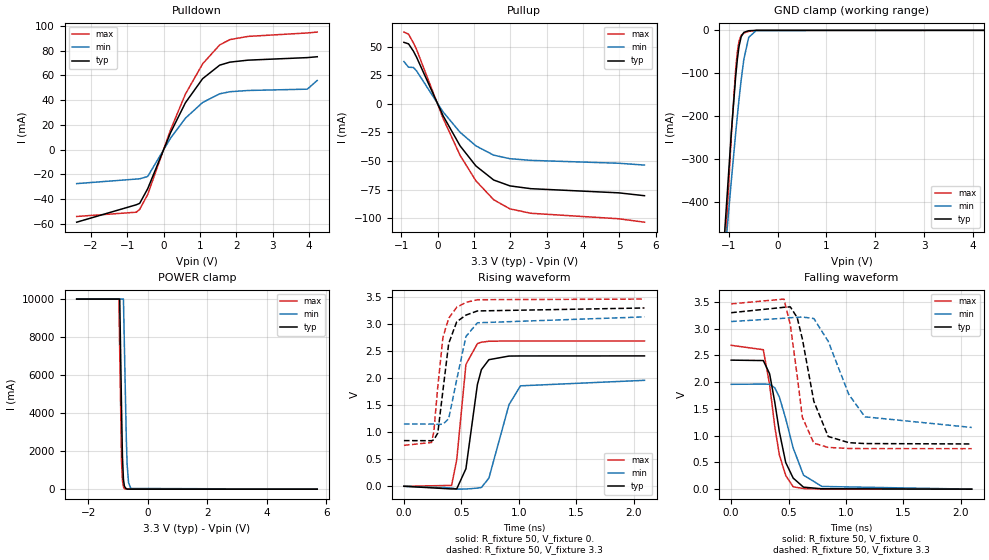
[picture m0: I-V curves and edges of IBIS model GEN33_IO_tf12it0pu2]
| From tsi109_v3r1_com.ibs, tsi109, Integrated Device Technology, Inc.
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|   MODEL GEN33_IO_tf12it0pu2
[Model]   GEN33_IO_tf12it0pu2
Model_type  I/O
C_comp 1.241p 1.168p 1.337p
Polarity   Non-Inverting
Enable   Active-High
|   typ   min   max
Vinl   =   0.800v
Vinh   =   2.000v
Vmeas  =   1.65V
[Model Spec]
[Temperature Range]   25   125   0
[Voltage Range] 3.3 3.135 3.465
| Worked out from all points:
|   slope of the pulldown table from 0 to 0.495 V, typ, clamps not added: 15.2 ohm
|   slope of the pullup table from 0 to 0.495 V, typ, clamps not added: 16.3 ohm
|   GND clamp passes 1 mA (typ) near -0.60 V on its own axis
|   POWER clamp passes 1 mA (typ) near -0.62 V on its own axis
|   rising waveform, R_fixture 50, V_fixture 0.: 20-80 % time 92.3ps typ, 147ps min, 70.9ps max; typ from 0 V to 2.41 V
|   rising waveform, R_fixture 50, V_fixture 3.3: 20-80 % time 89.9ps typ, 107ps min, 84.3ps max; typ from 0.845 V to 3.3 V
|   falling waveform, R_fixture 50, V_fixture 0.: 20-80 % time 121ps typ, 155ps min, 109ps max; typ from 2.41 V to 0 V
|   falling waveform, R_fixture 50, V_fixture 3.3: 20-80 % time 137ps typ, 233ps min, 99.2ps max; typ from 3.3 V to 0.845 V
[Pulldown]
-2.396V   -58.71mA   -27.53mA   -54.09mA
-756mV    -44.63mA   -23.86mA   -50.65mA
-662.3mV  -43.5mA    -23.65mA   -48.32mA
-441.4mV  -31.66mA   -21.77mA   -36.32mA
187.8mV   13.66mA    9.224mA    15.92mA
596.1mV   37.81mA    25.33mA    44.81mA
1.071V    57.3mA     38.06mA    69.3mA
1.54V     68.2mA     45.06mA    84.57mA
1.821V    70.64mA    46.71mA    88.84mA
2.316V    72.23mA    47.73mA    91.42mA
3.95V     74.3mA     48.8mA     94.22mA
4.224V    74.99mA    55.83mA    94.92mA
[Pullup]
-924.1mV  53.85mA    37.04mA    62.84mA
-796.9mV  52.53mA    32.1mA     61.01mA
-663mV    46.15mA    31.85mA    53.38mA
-576mV    40.84mA    28.84mA    47.65mA
153.6mV   -10.42mA   -7.05mA    -12.66mA
622.2mV   -36.8mA    -24.93mA   -45.11mA
1.057V    -54.36mA   -36.79mA   -67.37mA
1.546V    -66.67mA   -44.91mA   -83.94mA
1.994V    -71.82mA   -48.02mA   -91.95mA
2.57V     -74.26mA   -49.47mA   -95.79mA
4.986V    -77.9mA    -51.99mA   -100.6mA
5.696V    -80.41mA   -53.59mA   -103.6mA
[GND Clamp]
-2.396V   -2.986A    -2.401A    -3.708A
-1.125V   -539.1mA   -582mA     -620.1mA
-1.08V    -460.1mA   -522.3mA   -520.8mA
-947.6mV  -234.7mA   -348mA     -240.6mA
-859.2mV  -105.7mA   -238.3mA   -88.96mA
-826mV    -67.3mA    -199.3mA   -49.92mA
-792.9mV  -37.92mA   -162.2mA   -25.47mA
-748.6mV  -15.02mA   -116.3mA   -11.59mA
-693.4mV  -4.748mA   -67.77mA   -6.31mA
-593.9mV  -943.5uA   -16.33mA   -2.39mA
-439.1mV  -54.41uA   -469.2uA   -178.1uA
4.224V    0A         0A         0A
[Power Clamp]
-2.396V   10A        10A        10A
-976.6mV  10A        10A        10A
-947.8mV  10A        10A        7.204A
-885.5mV  4.099A     10A        1.393A
-856.7mV  1.716A     10A        455.5mA
-823.1mV  520.9mA    10A        118mA
-789.6mV  148.5mA    7.444A     32.62mA
-727.2mV  15.43mA    2.693A     6.055mA
-698.5mV  6.138mA    1.282A     4.069mA
-650.5mV  1.866mA    338.9mA    2.626mA
-573.8mV  505.4uA    37.48mA    1.307mA
5.696V    0A         0A         0A
[Ramp]
dV/dt_r 1.448/92.335p 1.177/146.677p 1.614/70.937p
dV/dt_f 1.473/136.643p 1.189/233.099p 1.625/99.238p
[Rising Waveform]
R_fixture = 50
V_fixture = 0.
0s        116.3uV    107.9uV    134.2uV
415ps     -49.61mV   -31.38mV   15.86mV
460ps     -47.89mV   -53.52mV   492.1mV
540ps     325.1mV    -51.22mV   2.255V
640ps     1.884V     -33.92mV   2.64V
675ps     2.16V      -21.85mV   2.667V
740ps     2.343V     151.1mV    2.684V
915ps     2.41V      1.51V      2.69V
1.015ns   2.412V     1.859V     2.69V
2.095ns   2.413V     1.961V     2.69V
[Rising Waveform]
R_fixture = 50
V_fixture = 3.3
V_fixture_min = 3.135
V_fixture_max = 3.465
0s        845.3mV    1.153V     757.4mV
240ps     843.4mV    1.152V     810.9mV
260ps     858mV      1.151V     998.7mV
295ps     985.8mV    1.146V     1.846V
340ps     1.777V     1.148V     2.76V
390ps     2.644V     1.251V     3.11V
460ps     3.045V     1.975V     3.314V
540ps     3.168V     2.771V     3.403V
640ps     3.245V     3.026V     3.453V
2.095ns   3.3V       3.135V     3.465V
[Falling Waveform]
R_fixture = 50
V_fixture = 0.
0s        2.413V     1.961V     2.69V
280ps     2.405V     1.965V     2.608V
335ps     2.157V     1.962V     1.952V
380ps     1.624V     1.895V     1.168V
420ps     1.072V     1.722V     639.3mV
475ps     499mV      1.318V     256.7mV
540ps     207.2mV    770.4mV    44.52mV
630ps     37.59mV    262.7mV    11.91mV
790ps     7.278mV    51.14mV    3.01mV
2.095ns   119uV      123.7uV    136.5uV
[Falling Waveform]
R_fixture = 50
V_fixture = 3.3
V_fixture_min = 3.135
V_fixture_max = 3.465
0s        3.3V       3.135V     3.465V
460ps     3.401V     3.196V     3.555V
515ps     3.409V     3.206V     3.079V
575ps     3.209V     3.214V     2.116V
620ps     2.81V      3.219V     1.343V
720ps     1.643V     3.191V     859.4mV
845ps     985.3mV    2.766V     780.4mV
1.025ns   869.7mV    1.769V     761.2mV
1.165ns   852.9mV    1.353V     758.4mV
2.095ns   845.4mV    1.154V     757.4mV
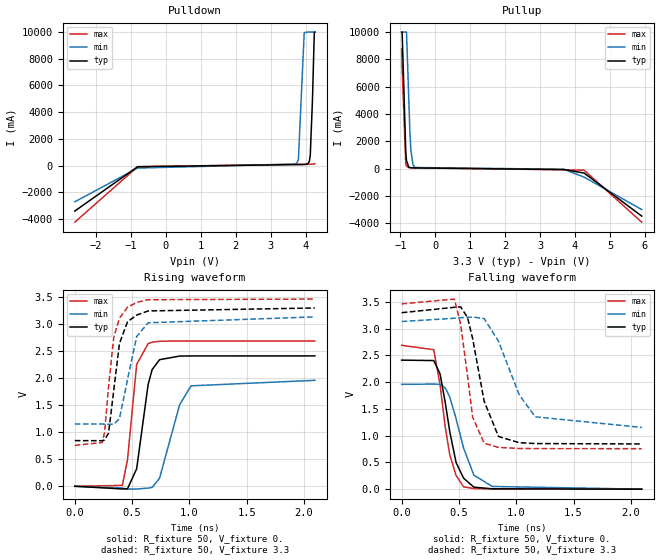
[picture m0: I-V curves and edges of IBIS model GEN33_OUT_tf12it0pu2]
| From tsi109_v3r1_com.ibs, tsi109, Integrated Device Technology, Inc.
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|   MODEL GEN33_OUT_tf12it0pu2
[Model]   GEN33_OUT_tf12it0pu2
Model_type  Output
C_comp 1.76p 1.691p 1.799p
Polarity   Non-Inverting
Enable   Active-High
Vmeas =   1.65V
|   typ   min   max
[Model Spec]
[Temperature Range]   25   125   0
[Voltage Range] 3.3 3.135 3.465
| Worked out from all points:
|   slope of the pulldown table from 0 to 0.495 V, typ, clamps not added: 15.3 ohm
|   slope of the pullup table from 0 to 0.495 V, typ, clamps not added: 16.3 ohm
|   rising waveform, R_fixture 50, V_fixture 0.: 20-80 % time 92.3ps typ, 147ps min, 70.9ps max; typ from 0 V to 2.41 V
|   rising waveform, R_fixture 50, V_fixture 3.3: 20-80 % time 89.9ps typ, 107ps min, 84.3ps max; typ from 0.845 V to 3.3 V
|   falling waveform, R_fixture 50, V_fixture 0.: 20-80 % time 121ps typ, 155ps min, 109ps max; typ from 2.41 V to 0 V
|   falling waveform, R_fixture 50, V_fixture 3.3: 20-80 % time 137ps typ, 233ps min, 99.2ps max; typ from 3.3 V to 0.845 V
[Pulldown]
-2.61V    -3.409A    -2.716A    -4.243A
-810.3mV  -87.58mA   -187.9mA   -85.68mA
3.727V    74mA       112.5mA    93.78mA
3.79V     74.17mA    432.2mA    93.9mA
3.957V    76.42mA    9.961A     94.66mA
4.061V    125.5mA    10A        96.1mA
4.103V    316.6mA    10A        96.93mA
4.13V     753.6mA    10A        97.62mA
4.193V    4.893A     10A        100.9mA
4.242V    9.621A     10A        115.9mA
4.248V    10A        10A        121.4mA
4.262V    10A        10A        138.9mA
[Pullup]
-962.4mV  10A        10A        8.778A
-948.5mV  10A        10A        7.327A
-844.3mV  1.168A     10A        338mA
-823.4mV  578.6mA    10A        181.5mA
-760.9mV  102.5mA    5.267A     72.24mA
-726.1mV  64.46mA    2.651A     63.17mA
-698.3mV  54.26mA    1.31A      59.62mA
-635.8mV  45.95mA    254.2mA    53.97mA
-580.2mV  41.67mA    74.14mA    49.33mA
3.686V    -76.24mA   -58.07mA   -98.5mA
4.263V    -336.6mA   -638.2mA   -127.6mA
5.91V     -3.49A     -3.011A    -3.936A
[Ramp]
dV/dt_r 1.448/92.339p 1.177/146.677p 1.614/70.93p
dV/dt_f 1.473/136.641p 1.189/233.088p 1.625/99.24p
[Rising Waveform]
R_fixture = 50
V_fixture = 0.
0s        116.3uV    107.9uV    134.2uV
415ps     -49.61mV   -31.38mV   15.86mV
460ps     -47.89mV   -53.52mV   492.1mV
540ps     325.1mV    -51.22mV   2.255V
640ps     1.884V     -33.92mV   2.64V
675ps     2.16V      -21.85mV   2.667V
740ps     2.343V     151.1mV    2.684V
915ps     2.41V      1.51V      2.69V
1.015ns   2.412V     1.859V     2.69V
2.095ns   2.413V     1.961V     2.69V
[Rising Waveform]
R_fixture = 50
V_fixture = 3.3
V_fixture_min = 3.135
V_fixture_max = 3.465
0s        845.3mV    1.153V     757.4mV
240ps     843.4mV    1.152V     810.9mV
260ps     858mV      1.151V     998.7mV
295ps     985.8mV    1.146V     1.846V
340ps     1.777V     1.148V     2.76V
390ps     2.644V     1.251V     3.11V
460ps     3.045V     1.975V     3.314V
540ps     3.168V     2.771V     3.403V
640ps     3.245V     3.026V     3.453V
2.095ns   3.3V       3.135V     3.465V
[Falling Waveform]
R_fixture = 50
V_fixture = 0.
0s        2.413V     1.961V     2.69V
280ps     2.405V     1.965V     2.608V
335ps     2.157V     1.962V     1.952V
380ps     1.624V     1.895V     1.168V
420ps     1.072V     1.722V     639.3mV
475ps     499mV      1.318V     256.7mV
540ps     207.2mV    770.4mV    44.52mV
630ps     37.59mV    262.7mV    11.91mV
790ps     7.278mV    51.14mV    3.01mV
2.095ns   119uV      123.7uV    136.5uV
[Falling Waveform]
R_fixture = 50
V_fixture = 3.3
V_fixture_min = 3.135
V_fixture_max = 3.465
0s        3.3V       3.135V     3.465V
460ps     3.401V     3.196V     3.555V
515ps     3.409V     3.206V     3.079V
575ps     3.209V     3.214V     2.116V
620ps     2.81V      3.219V     1.343V
720ps     1.643V     3.191V     859.4mV
845ps     985.3mV    2.766V     780.4mV
1.025ns   869.7mV    1.769V     761.2mV
1.165ns   852.9mV    1.353V     758.4mV
2.095ns   845.4mV    1.154V     757.4mV
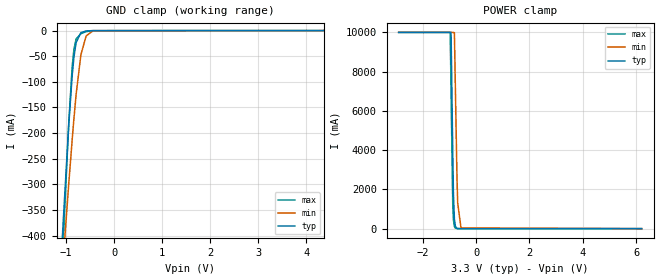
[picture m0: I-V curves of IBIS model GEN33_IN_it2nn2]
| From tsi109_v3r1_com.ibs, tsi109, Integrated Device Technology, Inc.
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|   MODEL GEN33_IN_it2nn2
[Model]   GEN33_IN_it2nn2
Model_type  Input
C_comp 2.394p 2.25p 2.584p
Polarity   Non-Inverting
Enable   Active-High
|   typ   min   max
Vinl   =   0.800v
Vinh   =   2.000v
[Model Spec]
[Temperature Range]   25   125   0
[Voltage Range] 3.3 3.135 3.465
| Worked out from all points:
|   GND clamp passes 1 mA (typ) near -0.60 V on its own axis
|   POWER clamp passes 1 mA (typ) near -0.61 V on its own axis
[GND Clamp]
-2.907V   -3.934A    -3.096A    -4.907A
-1.119V   -473.9mA   -524.3mA   -539.4mA
-1.092V   -425.8mA   -487.9mA   -479.1mA
-1.064V   -378.4mA   -451.8mA   -419.7mA
-946.3mV  -185.7mA   -300.1mA   -181.9mA
-873.7mV  -87.95mA   -212.7mA   -70.4mA
-837.4mV  -51.8mA    -171.9mA   -36.36mA
-792mV    -23.41mA   -124.8mA   -16.35mA
-692.2mV  -3.96mA    -47.09mA   -6.041mA
-583.3mV  -769.3uA   -10.53mA   -2.088mA
-438.1mV  -39.28uA   -361.9uA   -155.8uA
4.367V    0A         0A         0A
[Power Clamp]
-2.907V   10A        10A        10A
-974.8mV  10A        10A        10A
-948.4mV  10A        10A        7.702A
-939.5mV  9.811A     10A        6.784A
-877.8mV  3.822A     10A        1.228A
-851.3mV  1.685A     10A        435.7mA
-816.1mV  479.8mA    9.979A     105.8mA
-780.8mV  128.4mA    7.266A     27.84mA
-719mV    13.52mA    2.586A     5.592mA
-692.6mV  5.866mA    1.305A     3.903mA
-569.1mV  465uA      39.5mA     1.235mA
6.207V    0A         0A         0A
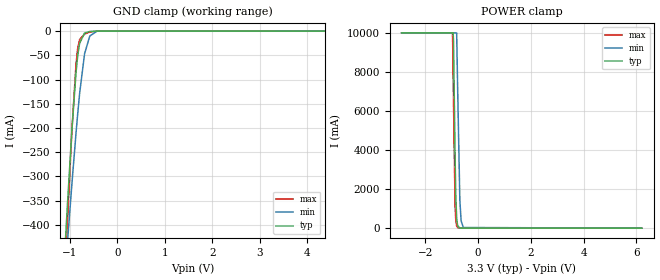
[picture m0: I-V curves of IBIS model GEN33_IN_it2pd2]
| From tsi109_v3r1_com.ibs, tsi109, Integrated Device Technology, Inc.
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|   MODEL GEN33_IN_it2pd2
[Model]   GEN33_IN_it2pd2
Model_type  Input
C_comp 2.4p 2.257p 2.589p
Polarity   Non-Inverting
Enable   Active-High
|   typ   min   max
Vinl   =   0.800v
Vinh   =   2.000v
[Model Spec]
[Temperature Range]   25   125   0
[Voltage Range] 3.3 3.135 3.465
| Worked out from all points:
|   GND clamp passes 1 mA (typ) near -0.60 V on its own axis
|   POWER clamp passes 1 mA (typ) near -0.61 V on its own axis
[GND Clamp]
-2.907V   -3.934A    -3.096A    -4.907A
-1.122V   -479.1mA   -528.2mA   -546mA
-1.087V   -417.6mA   -481.6mA   -468.7mA
-1.058V   -367.2mA   -443.1mA   -405.6mA
-958.9mV  -204.8mA   -315.8mA   -205mA
-871.7mV  -85.61mA   -210.4mA   -68.08mA
-836.8mV  -51.29mA   -171.2mA   -35.92mA
-796.1mV  -25.19mA   -128.8mA   -17.4mA
-691.4mV  -3.929mA   -46.69mA   -6.025mA
-581mV    -763.1uA   -10.11mA   -2.05mA
-429.8mV  -52.97uA   -299.1uA   -153uA
4.367V    0A         0A         0A
[Power Clamp]
-2.907V   10A        10A        10A
-973.6mV  10A        10A        10A
-949.4mV  10A        10A        7.815A
-937.4mV  9.599A     10A        6.557A
-877mV    3.74A      10A        1.189A
-852.8mV  1.77A      10A        463mA
-816.5mV  488.7mA    10A        108.1mA
-780.3mV  126.1mA    7.231A     27.49mA
-695.7mV  6.492mA    1.421A     4.106mA
-647.4mV  1.907mA    373.7mA    2.629mA
-562.8mV  470.3uA    32.97mA    1.219mA
6.207V    0A         0A         0A
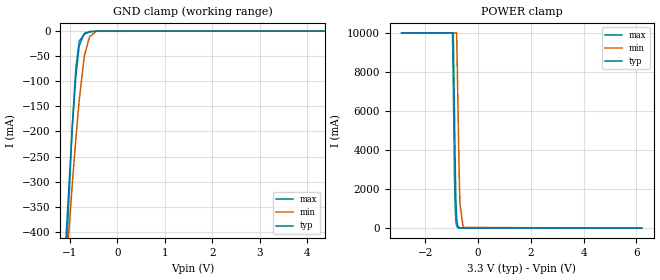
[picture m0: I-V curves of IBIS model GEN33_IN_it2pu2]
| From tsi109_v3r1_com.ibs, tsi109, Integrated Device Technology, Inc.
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|   MODEL GEN33_IN_it2pu2
[Model]   GEN33_IN_it2pu2
Model_type  Input
C_comp 2.388p 2.242p 2.58p
Polarity   Non-Inverting
Enable   Active-High
|   typ   min   max
Vinl   =   0.800v
Vinh   =   2.000v
[Model Spec]
[Temperature Range]   25   125   0
[Voltage Range] 3.3 3.135 3.465
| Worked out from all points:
|   GND clamp passes 1 mA (typ) near -0.60 V on its own axis
|   POWER clamp passes 1 mA (typ) near -0.61 V on its own axis
[GND Clamp]
-2.907V   -3.934A    -3.096A    -4.907A
-1.131V   -496.2mA   -541.1mA   -567.4mA
-1.119V   -474.7mA   -524.9mA   -540.4mA
-1.095V   -432mA     -492.6mA   -486.8mA
-1.083V   -410.9mA   -476.5mA   -460.3mA
-950.1mV  -191.4mA   -304.8mA   -188.7mA
-877.6mV  -92.52mA   -217.3mA   -75.23mA
-805.2mV  -29.73mA   -137.9mA   -20.17mA
-696.5mV  -4.247mA   -49.47mA   -6.261mA
-587.8mV  -839.7uA   -11.35mA   -2.22mA
-442.9mV  -58.38uA   -420.2uA   -192.4uA
4.367V    0A         0A         0A
[Power Clamp]
-2.907V   10A        10A        10A
-975.5mV  10A        10A        10A
-946.4mV  10A        10A        7.5A
-899.9mV  5.961A     10A        2.703A
-876.6mV  3.708A     10A        1.174A
-847.5mV  1.482A     10A        374.1mA
-818.5mV  523.6mA    10A        116.9mA
-783.6mV  142.3mA    7.48A      30.78mA
-719.6mV  13.83mA    2.622A     5.651mA
-690.5mV  5.49mA     1.235A     3.828mA
-568.3mV  466.8uA    38.74mA    1.233mA
6.207V    0A         0A         0A
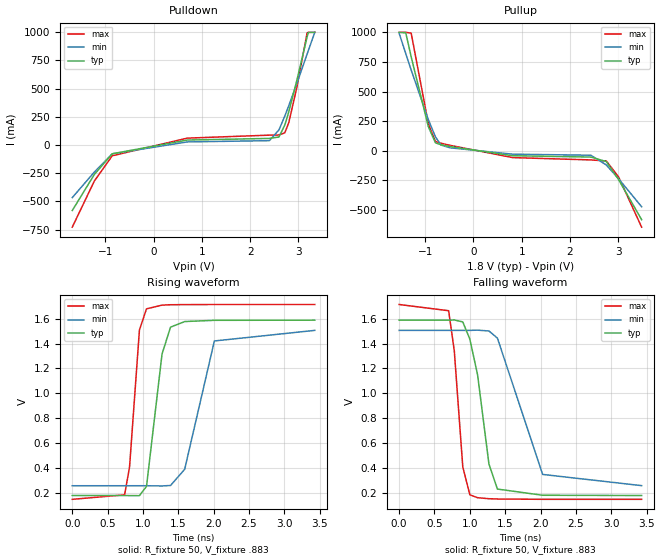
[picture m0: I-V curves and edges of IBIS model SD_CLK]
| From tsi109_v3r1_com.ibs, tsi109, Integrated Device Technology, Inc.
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|   MODEL SD_CLK
[Model]   SD_CLK
Model_type  Output
Polarity   Non-Inverting
Enable   Active-High
|   typ   min   max
C_comp 3.3p 3.205p 3.473p
Cref  = 20pF
Vmeas = 0.9v
[Model Spec]
[Temperature Range]   25   125   0
[Voltage Range] 1.8 1.79 1.89
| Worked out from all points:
|   slope of the pulldown table from 0 to 0.27 V, typ, clamps not added: 13.3 ohm
|   slope of the pullup table from 0 to 0.27 V, typ, clamps not added: 15.4 ohm
|   rising waveform, R_fixture 50, V_fixture .883: 20-80 % time 155ps typ, 240ps min, 111ps max; typ from 0.179 V to 1.59 V
|   falling waveform, R_fixture 50, V_fixture .883: 20-80 % time 211ps typ, 386ps min, 121ps max; typ from 1.59 V to 0.179 V
[Pulldown]
-1.684V   -581.6mA   -466.6mA   -729.1mA
-1.227V   -261.6mA   -240.5mA   -319.7mA
-855.8mV  -77.74mA   -78.44mA   -95.78mA
698.5mV   43.97mA    27.46mA    60.95mA
2.4V      58.36mA    38.59mA    87.46mA
2.598V    71.03mA    134mA      88.69mA
2.72V     177.3mA    256.8mA    108.4mA
2.801V    292.8mA    347.8mA    197.3mA
2.969V    574.1mA    545.8mA    510.8mA
3.182V    959.4mA    807.4mA    995.1mA
3.208V    999.4mA    839mA      1A
3.34V     1A         1A         1A
[Pullup]
-1.54V    1A         991.8mA    1A
-1.403V   995.8mA    820.5mA    1A
-1.291V   793.6mA    682.5mA    993.4mA
-935.3mV  204mA      263.5mA    230.2mA
-788mV    67.71mA    117.9mA    79.31mA
-671.2mV  50.72mA    48.2mA     64.23mA
-483.3mV  36.1mA     25.52mA    46.08mA
812mV     -41.37mA   -28.2mA    -57.01mA
2.432V    -52.68mA   -37.15mA   -76.75mA
2.752V    -90.67mA   -119.2mA   -85.66mA
3.006V    -242.5mA   -235.7mA   -219.6mA
3.484V    -580.9mA   -471.9mA   -644.1mA
[Ramp]
dV/dt_r .845/154.678p .749/240.064p .939/110.93p
dV/dt_f .845/210.589p .749/385.819p .939/121.27p
[Rising Waveform]
R_fixture = 50
V_fixture = .883
V_fixture_min = .882
V_fixture_max = .931
0s        179.2mV    257.7mV    148.5mV
740ps     179.2mV    257.7mV    184.6mV
810ps     178.4mV    257.7mV    406.6mV
950ps     178.3mV    257.8mV    1.509V
1.05ns    252.2mV    257.6mV    1.679V
1.27ns    1.317V     256.1mV    1.709V
1.39ns    1.532V     259.8mV    1.712V
1.59ns    1.577V     389.7mV    1.713V
2.01ns    1.587V     1.421V     1.714V
3.43ns    1.588V     1.506V     1.714V
[Falling Waveform]
R_fixture = 50
V_fixture = .883
V_fixture_min = .882
V_fixture_max = .931
0s        1.588V     1.506V     1.714V
700ps     1.588V     1.506V     1.664V
780ps     1.59V      1.506V     1.342V
900ps     1.574V     1.506V     410.3mV
1ns       1.436V     1.506V     185mV
1.11ns    1.147V     1.508V     161.6mV
1.27ns    432.3mV    1.501V     153.5mV
1.39ns    231.1mV    1.444V     151.1mV
2.03ns    181.2mV    348.6mV    148.6mV
3.43ns    179.2mV    258.6mV    148.5mV
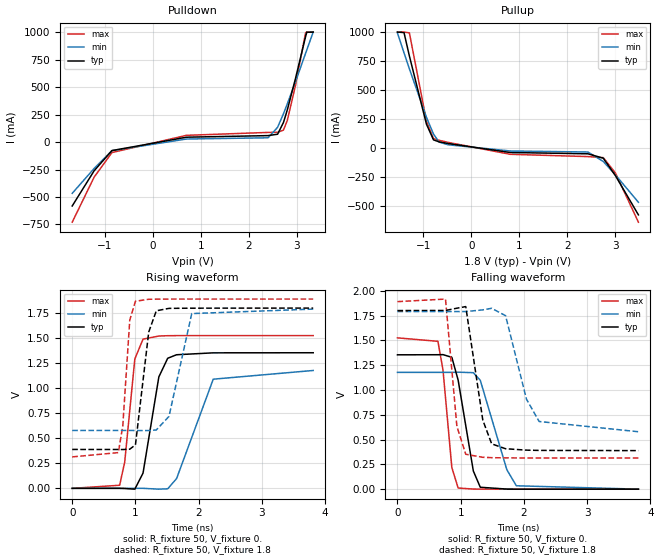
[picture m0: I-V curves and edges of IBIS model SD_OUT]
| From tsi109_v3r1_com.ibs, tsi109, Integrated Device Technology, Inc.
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|   MODEL SD_OUT
[Model]   SD_OUT
Model_type  Output
Polarity   Non-Inverting
Enable   Active-High
|   typ   min   max
C_comp 2.843p 2.708p 2.978p
Cref  = 20pF
Vmeas = 0.9v
[Model Spec]
[Temperature Range]   25   125   0
[Voltage Range] 1.8 1.79 1.89
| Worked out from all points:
|   slope of the pulldown table from 0 to 0.27 V, typ, clamps not added: 13.3 ohm
|   slope of the pullup table from 0 to 0.27 V, typ, clamps not added: 15.4 ohm
|   rising waveform, R_fixture 50, V_fixture 0.: 20-80 % time 205ps typ, 349ps min, 137ps max; typ from 0 V to 1.35 V
|   rising waveform, R_fixture 50, V_fixture 1.8: 20-80 % time 121ps typ, 175ps min, 93.3ps max; typ from 0.389 V to 1.8 V
|   falling waveform, R_fixture 50, V_fixture 0.: 20-80 % time 211ps typ, 322ps min, 129ps max; typ from 1.35 V to 0 V
|   falling waveform, R_fixture 50, V_fixture 1.8: 20-80 % time 164ps typ, 287ps min, 113ps max; typ from 1.8 V to 0.389 V
[Pulldown]
-1.684V   -581.6mA   -466.6mA   -729.1mA
-1.227V   -261.6mA   -240.5mA   -319.7mA
-855.8mV  -77.74mA   -78.44mA   -95.78mA
698.5mV   43.97mA    27.46mA    60.95mA
2.4V      58.36mA    38.59mA    87.46mA
2.598V    71.03mA    134mA      88.69mA
2.72V     177.3mA    256.8mA    108.4mA
2.801V    292.8mA    347.8mA    197.3mA
2.969V    574.1mA    545.8mA    510.8mA
3.182V    959.4mA    807.4mA    995.1mA
3.208V    999.4mA    839mA      1A
3.34V     1A         1A         1A
[Pullup]
-1.54V    1A         991.8mA    1A
-1.403V   995.8mA    820.5mA    1A
-1.291V   793.6mA    682.5mA    993.4mA
-935.3mV  204mA      263.5mA    230.2mA
-788mV    67.71mA    117.9mA    79.31mA
-671.2mV  50.72mA    48.2mA     64.23mA
-483.3mV  36.1mA     25.52mA    46.08mA
812mV     -41.37mA   -28.2mA    -57.01mA
2.432V    -52.68mA   -37.15mA   -76.75mA
2.752V    -90.67mA   -119.2mA   -85.66mA
3.006V    -242.5mA   -235.7mA   -219.6mA
3.484V    -580.9mA   -471.9mA   -644.1mA
[Ramp]
dV/dt_r .812/205.333p .707/348.983p .915/137.035p
dV/dt_f .847/163.919p .727/287.542p .946/112.729p
[Rising Waveform]
R_fixture = 50
V_fixture = 0.
0s        0V         0V         0V
750ps     198.8uV    9.682uV    30.91mV
830ps     -1.556mV   53.73uV    261.1mV
990ps     -8.183mV   215.8uV    1.292V
1.12ns    152.3mV    172.1uV    1.49V
1.37ns    1.113V     -8.101mV   1.521V
1.51ns    1.299V     -4.501mV   1.524V
1.65ns    1.334V     97.09mV    1.525V
2.23ns    1.353V     1.09V      1.525V
3.81ns    1.354V     1.177V     1.525V
[Rising Waveform]
R_fixture = 50
V_fixture = 1.8
V_fixture_min = 1.79
V_fixture_max = 1.89
0s        388.5mV    577.9mV    314.1mV
730ps     388.1mV    577.9mV    356.9mV
800ps     387.6mV    577.9mV    625.7mV
910ps     390.9mV    577.9mV    1.68V
1ns       434.4mV    577.6mV    1.868V
1.21ns    1.561V     576.7mV    1.888V
1.33ns    1.773V     583mV      1.889V
1.53ns    1.797V     718.3mV    1.89V
1.89ns    1.799V     1.745V     1.89V
3.81ns    1.8V       1.79V      1.89V
[Falling Waveform]
R_fixture = 50
V_fixture = 0.
0s        1.354V     1.177V     1.525V
640ps     1.355V     1.177V     1.49V
720ps     1.356V     1.177V     1.203V
860ps     1.329V     1.177V     217.8mV
960ps     1.099V     1.179V     11.46mV
1.2ns     183.2mV    1.174V     1.231mV
1.31ns    19.42mV    1.097V     666.5uV
1.73ns    787.2uV    195.5mV    85.24uV
1.88ns    409.6uV    34.25mV    40.13uV
3.81ns    -532.6nV   23.37uV    0V
[Falling Waveform]
R_fixture = 50
V_fixture = 1.8
V_fixture_min = 1.79
V_fixture_max = 1.89
0s        1.8V       1.79V      1.89V
760ps     1.801V     1.79V      1.916V
940ps     1.824V     1.79V      631.8mV
1.08ns    1.84V      1.79V      352mV
1.35ns    695.1mV    1.807V     321.1mV
1.49ns    456.6mV    1.823V     317.5mV
1.71ns    407.5mV    1.748V     315.2mV
2.04ns    393.3mV    907.4mV    314.3mV
2.24ns    390.6mV    682.1mV    314.2mV
3.81ns    388.5mV    578.8mV    314.1mV
